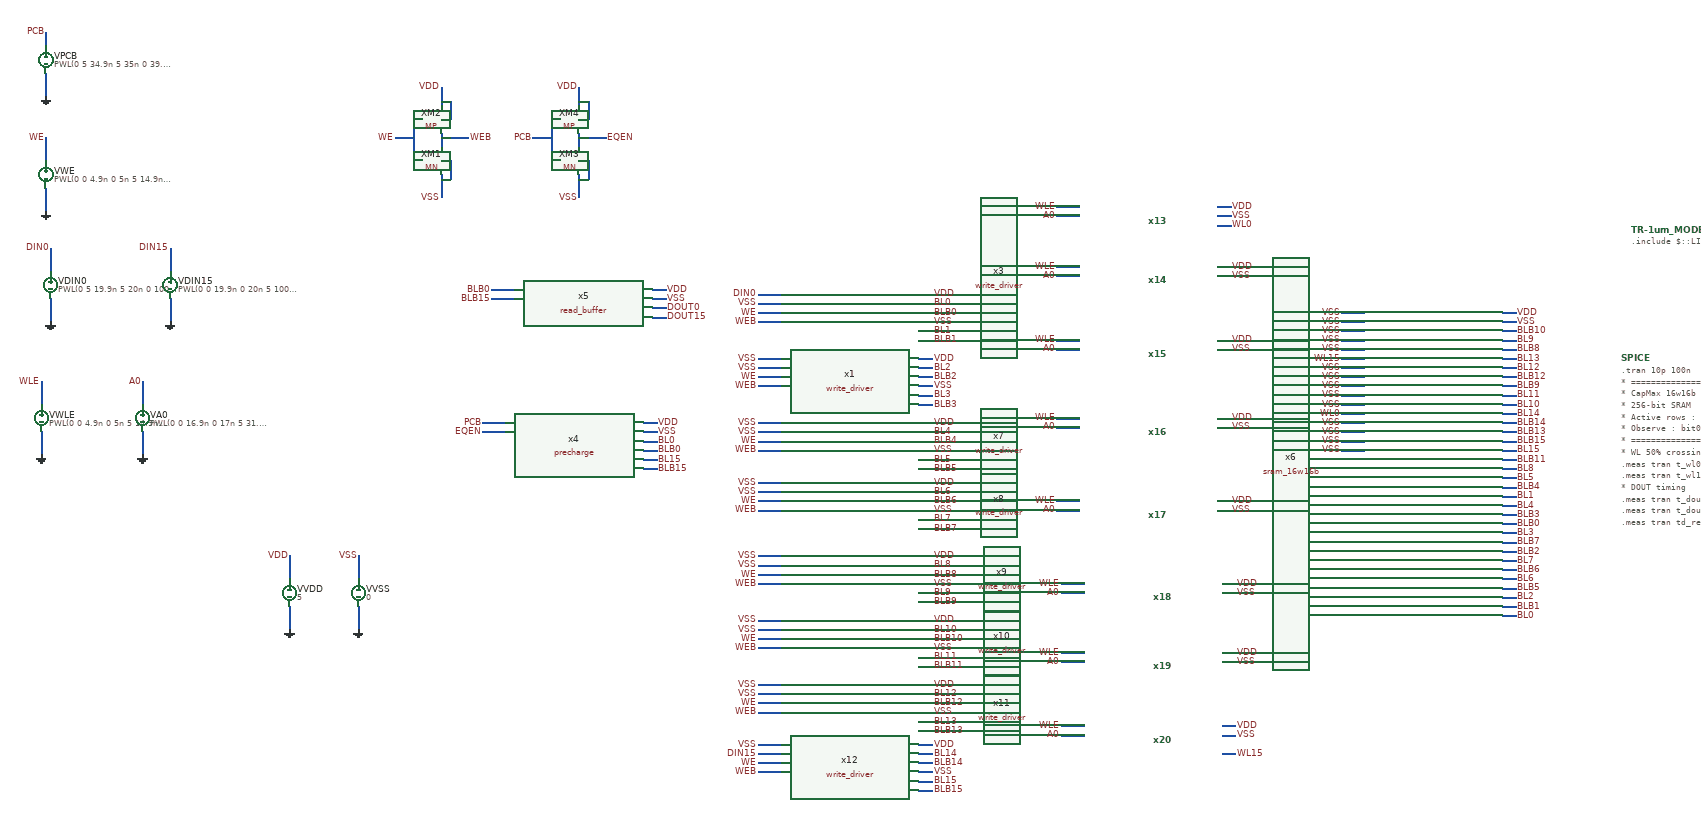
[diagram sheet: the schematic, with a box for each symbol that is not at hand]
v {xschem version=3.4.8RC file_version=1.3}
G {}
K {}
V {}
S {}
F {}
E {}
N 2980 -1010 3030 -1010 {lab=WL0}
N 2980 -990 3030 -990 {lab=WL1}
N 3330 -990 3360 -990 {lab=VSS}
N 3330 -1010 3360 -1010 {lab=VDD}
N 690 -370 690 -320 {lab=0}
N 690 -480 690 -430 {lab=VDD}
N 3330 -730 3360 -730 {lab=BLB15}
N 3330 -690 3360 -690 {lab=BLB11}
N 3330 -930 3360 -930 {lab=BLB8}
N 170 -1040 170 -990 {lab=0}
N 170 -1150 170 -1100 {lab=DIN0}
N 840 -370 840 -320 {lab=0}
N 840 -480 840 -430 {lab=VSS}
N 160 -1280 160 -1230 {lab=0}
N 160 -1390 160 -1340 {lab=WE}
N 160 -1620 160 -1590 {lab=PCB}
N 160 -1530 160 -1480 {lab=0}
N 150 -750 150 -700 {lab=0}
N 150 -860 150 -810 {lab=WLE}
N 370 -750 370 -700 {lab=0}
N 370 -860 370 -810 {lab=A0}
N 2060 -1050 2090 -1050 {lab=VDD}
N 2060 -990 2090 -990 {lab=VSS}
N 1710 -1010 1760 -1010 {lab=WE}
N 1710 -990 1760 -990 {lab=WEB}
N 2060 -1030 2090 -1030 {lab=BL0}
N 2060 -1010 2090 -1010 {lab=BLB0}
N 2060 -970 2090 -970 {lab=BL1}
N 2060 -950 2090 -950 {lab=BLB1}
N 1710 -1050 1760 -1050 {lab=DIN0}
N 1710 -1030 1760 -1030 {lab=VSS}
N 430 -1040 430 -990 {lab=0}
N 430 -1150 430 -1100 {lab=DIN15}
N 1110 -770 1160 -770 {lab=PCB}
N 1110 -750 1160 -750 {lab=EQEN}
N 1460 -770 1490 -770 {lab=VDD}
N 1460 -750 1490 -750 {lab=VSS}
N 1460 -730 1490 -730 {lab=BL0}
N 1460 -710 1490 -710 {lab=BLB0}
N 1460 -690 1490 -690 {lab=BL15}
N 1460 -670 1490 -670 {lab=BLB15}
N 1480 -1060 1510 -1060 {lab=VDD}
N 1480 -1040 1510 -1040 {lab=VSS}
N 1480 -1020 1510 -1020 {lab=DOUT0}
N 1480 -1000 1510 -1000 {lab=DOUT15}
N 1130 -1060 1180 -1060 {lab=BLB0}
N 1130 -1040 1180 -1040 {lab=BLB15}
N 1020 -1400 1020 -1370 {lab=WEB}
N 1020 -1310 1020 -1260 {lab=VSS}
N 1020 -1340 1040 -1340 {lab=VSS}
N 1040 -1340 1040 -1300 {lab=VSS}
N 1020 -1300 1040 -1300 {lab=VSS}
N 1020 -1500 1020 -1460 {lab=VDD}
N 960 -1430 980 -1430 {lab=WE}
N 960 -1430 960 -1340 {lab=WE}
N 960 -1340 980 -1340 {lab=WE}
N 1020 -1390 1080 -1390 {lab=WEB}
N 920 -1390 960 -1390 {lab=WE}
N 1020 -1430 1040 -1430 {lab=VDD}
N 1040 -1470 1040 -1430 {lab=VDD}
N 1020 -1470 1040 -1470 {lab=VDD}
N 1320 -1400 1320 -1370 {lab=EQEN}
N 1320 -1310 1320 -1260 {lab=VSS}
N 1320 -1340 1340 -1340 {lab=VSS}
N 1340 -1340 1340 -1300 {lab=VSS}
N 1320 -1300 1340 -1300 {lab=VSS}
N 1320 -1500 1320 -1460 {lab=VDD}
N 1260 -1430 1280 -1430 {lab=PCB}
N 1260 -1430 1260 -1340 {lab=PCB}
N 1260 -1340 1280 -1340 {lab=PCB}
N 1320 -1390 1380 -1390 {lab=EQEN}
N 1220 -1390 1260 -1390 {lab=PCB}
N 1320 -1430 1340 -1430 {lab=VDD}
N 1340 -1470 1340 -1430 {lab=VDD}
N 1320 -1470 1340 -1470 {lab=VDD}
N 3330 -670 3360 -670 {lab=BL8}
N 3330 -870 3360 -870 {lab=BLB12}
N 3330 -950 3360 -950 {lab=BL9}
N 3330 -970 3360 -970 {lab=BLB10}
N 3330 -830 3360 -830 {lab=BL11}
N 3330 -810 3360 -810 {lab=BL10}
N 3330 -790 3360 -790 {lab=BL14}
N 3330 -750 3360 -750 {lab=BLB13}
N 3330 -890 3360 -890 {lab=BL12}
N 3330 -850 3360 -850 {lab=BLB9}
N 3330 -770 3360 -770 {lab=BLB14}
N 3330 -710 3360 -710 {lab=BL15}
N 3330 -910 3360 -910 {lab=BL13}
N 2060 -910 2090 -910 {lab=VDD}
N 2060 -850 2090 -850 {lab=VSS}
N 1710 -870 1760 -870 {lab=WE}
N 1710 -850 1760 -850 {lab=WEB}
N 2060 -890 2090 -890 {lab=BL2}
N 2060 -870 2090 -870 {lab=BLB2}
N 2060 -830 2090 -830 {lab=BL3}
N 2060 -810 2090 -810 {lab=BLB3}
N 1710 -910 1760 -910 {lab=VSS}
N 1710 -890 1760 -890 {lab=VSS}
N 2060 -770 2090 -770 {lab=VDD}
N 2060 -710 2090 -710 {lab=VSS}
N 1710 -730 1760 -730 {lab=WE}
N 1710 -710 1760 -710 {lab=WEB}
N 2060 -750 2090 -750 {lab=BL4}
N 2060 -730 2090 -730 {lab=BLB4}
N 2060 -690 2090 -690 {lab=BL5}
N 2060 -670 2090 -670 {lab=BLB5}
N 1710 -770 1760 -770 {lab=VSS}
N 1710 -750 1760 -750 {lab=VSS}
N 2060 -640 2090 -640 {lab=VDD}
N 2060 -580 2090 -580 {lab=VSS}
N 1710 -600 1760 -600 {lab=WE}
N 1710 -580 1760 -580 {lab=WEB}
N 2060 -620 2090 -620 {lab=BL6}
N 2060 -600 2090 -600 {lab=BLB6}
N 2060 -560 2090 -560 {lab=BL7}
N 2060 -540 2090 -540 {lab=BLB7}
N 1710 -640 1760 -640 {lab=VSS}
N 1710 -620 1760 -620 {lab=VSS}
N 3330 -590 3360 -590 {lab=BL4}
N 3330 -550 3360 -550 {lab=BLB0}
N 3330 -530 3360 -530 {lab=BL3}
N 3330 -650 3360 -650 {lab=BL5}
N 3330 -610 3360 -610 {lab=BL1}
N 3330 -630 3360 -630 {lab=BLB4}
N 3330 -570 3360 -570 {lab=BLB3}
N 3330 -510 3360 -510 {lab=BLB7}
N 3330 -430 3360 -430 {lab=BL6}
N 3330 -390 3360 -390 {lab=BL2}
N 3330 -370 3360 -370 {lab=BLB1}
N 3330 -490 3360 -490 {lab=BLB2}
N 3330 -450 3360 -450 {lab=BLB6}
N 3330 -470 3360 -470 {lab=BL7}
N 3330 -410 3360 -410 {lab=BLB5}
N 3330 -350 3360 -350 {lab=BL0}
N 2060 -480 2090 -480 {lab=VDD}
N 2060 -420 2090 -420 {lab=VSS}
N 1710 -440 1760 -440 {lab=WE}
N 1710 -420 1760 -420 {lab=WEB}
N 2060 -460 2090 -460 {lab=BL8}
N 2060 -440 2090 -440 {lab=BLB8}
N 2060 -400 2090 -400 {lab=BL9}
N 2060 -380 2090 -380 {lab=BLB9}
N 1710 -480 1760 -480 {lab=VSS}
N 1710 -460 1760 -460 {lab=VSS}
N 2060 -340 2090 -340 {lab=VDD}
N 2060 -280 2090 -280 {lab=VSS}
N 1710 -300 1760 -300 {lab=WE}
N 1710 -280 1760 -280 {lab=WEB}
N 2060 -320 2090 -320 {lab=BL10}
N 2060 -300 2090 -300 {lab=BLB10}
N 2060 -260 2090 -260 {lab=BL11}
N 2060 -240 2090 -240 {lab=BLB11}
N 1710 -340 1760 -340 {lab=VSS}
N 1710 -320 1760 -320 {lab=VSS}
N 2060 -200 2090 -200 {lab=VDD}
N 2060 -140 2090 -140 {lab=VSS}
N 1710 -160 1760 -160 {lab=WE}
N 1710 -140 1760 -140 {lab=WEB}
N 2060 -180 2090 -180 {lab=BL12}
N 2060 -160 2090 -160 {lab=BLB12}
N 2060 -120 2090 -120 {lab=BL13}
N 2060 -100 2090 -100 {lab=BLB13}
N 1710 -200 1760 -200 {lab=VSS}
N 1710 -180 1760 -180 {lab=VSS}
N 2060 -70 2090 -70 {lab=VDD}
N 2060 -10 2090 -10 {lab=VSS}
N 1710 -30 1760 -30 {lab=WE}
N 1710 -10 1760 -10 {lab=WEB}
N 2060 -50 2090 -50 {lab=BL14}
N 2060 -30 2090 -30 {lab=BLB14}
N 2060 10 2090 10 {lab=BL15}
N 2060 30 2090 30 {lab=BLB15}
N 1710 -70 1760 -70 {lab=VSS}
N 1710 -50 1760 -50 {lab=DIN15}
N 2980 -970 3030 -970 {lab=WL0}
N 2980 -950 3030 -950 {lab=WL1}
N 2980 -930 3030 -930 {lab=WL0}
N 2980 -910 3030 -910 {lab=WL1}
N 2980 -890 3030 -890 {lab=WL0}
N 2980 -870 3030 -870 {lab=WL1}
N 2980 -850 3030 -850 {lab=WL0}
N 2980 -830 3030 -830 {lab=WL1}
N 2980 -810 3030 -810 {lab=WL0}
N 2980 -790 3030 -790 {lab=WL1}
N 2980 -770 3030 -770 {lab=WL0}
N 2980 -750 3030 -750 {lab=WL1}
N 2980 -730 3030 -730 {lab=WL0}
N 2980 -710 3030 -710 {lab=WL1}
N 2360 -1240 2410 -1240 {lab=WLE}
N 2360 -1220 2410 -1220 {lab=A0}
N 2710 -1240 2740 -1240 {lab=VDD}
N 2710 -1220 2740 -1220 {lab=VSS}
N 2710 -1200 2740 -1200 {lab=WL0}
N 2360 -1110 2410 -1110 {lab=WLE}
N 2360 -1090 2410 -1090 {lab=A0}
N 2710 -1110 2740 -1110 {lab=VDD}
N 2360 -950 2410 -950 {lab=WLE}
N 2360 -930 2410 -930 {lab=A0}
N 2710 -950 2740 -950 {lab=VDD}
N 2710 -930 2740 -930 {lab=VSS}
N 2360 -780 2410 -780 {lab=WLE}
N 2360 -760 2410 -760 {lab=A0}
N 2710 -780 2740 -780 {lab=VDD}
N 2710 -760 2740 -760 {lab=VSS}
N 2360 -600 2410 -600 {lab=WLE}
N 2360 -580 2410 -580 {lab=A0}
N 2710 -600 2740 -600 {lab=VDD}
N 2710 -580 2740 -580 {lab=VSS}
N 2370 -420 2420 -420 {lab=WLE}
N 2370 -400 2420 -400 {lab=A0}
N 2720 -420 2750 -420 {lab=VDD}
N 2720 -400 2750 -400 {lab=VSS}
N 2370 -270 2420 -270 {lab=WLE}
N 2370 -250 2420 -250 {lab=A0}
N 2720 -270 2750 -270 {lab=VDD}
N 2720 -250 2750 -250 {lab=VSS}
N 2370 -110 2420 -110 {lab=WLE}
N 2370 -90 2420 -90 {lab=A0}
N 2720 -110 2750 -110 {lab=VDD}
N 2720 -90 2750 -90 {lab=VSS}
N 2720 -50 2750 -50 {lab=WL15}
N 2710 -1090 2740 -1090 {lab=VSS}
C {devices/lab_pin.sym} 2980 -1010 0 0 {name=p1 sig_type=std_logic lab=VSS}
C {devices/lab_pin.sym} 2980 -990 0 0 {name=p2 sig_type=std_logic lab=VSS}
C {devices/lab_pin.sym} 3360 -1010 0 1 {name=p3 sig_type=std_logic lab=VDD}
C {devices/vsource.sym} 690 -400 0 0 {name=VVDD value=5 savecurrent=false}
C {devices/gnd.sym} 690 -320 0 0 {name=l4 lab=0}
C {devices/lab_pin.sym} 690 -480 0 0 {name=p6 sig_type=std_logic lab=VDD}
C {devices/lab_pin.sym} 3360 -730 0 1 {name=p8 sig_type=std_logic lab=BLB15}
C {devices/lab_pin.sym} 3360 -690 0 1 {name=p9 sig_type=std_logic lab=BLB11}
C {devices/lab_pin.sym} 3360 -930 0 1 {name=p10 sig_type=std_logic lab=BLB8}
C {devices/vsource.sym} 170 -1070 0 0 {name=VDIN0 value="PWL(0 5 19.9n 5 20n 0 100n 0)" savecurrent=false}
C {devices/gnd.sym} 170 -990 0 0 {name=l5 lab=0}
C {devices/lab_pin.sym} 170 -1150 0 0 {name=p35 sig_type=std_logic lab=DIN0}
C {devices/vsource.sym} 840 -400 0 0 {name=VVSS value=0 savecurrent=false}
C {devices/gnd.sym} 840 -320 0 0 {name=l9 lab=0}
C {devices/lab_pin.sym} 840 -480 0 0 {name=p43 sig_type=std_logic lab=VSS}
C {devices/lab_pin.sym} 3360 -990 0 1 {name=p39 sig_type=std_logic lab=VSS}
C {devices/vsource.sym} 160 -1310 0 0 {name=VWE value="PWL(0 0 4.9n 0 5n 5 14.9n 5 15n 0 19.9n 0 20n 5 29.9n 5 30n 0 100n 0)" savecurrent=false}
C {devices/gnd.sym} 160 -1230 0 0 {name=l1 lab=0}
C {devices/lab_pin.sym} 160 -1390 0 0 {name=p40 sig_type=std_logic lab=WE}
C {devices/code.sym} 3610 -1190 0 0 {name=TR-1um_MODELS
only_toplevel=true
format="tcleval( @value )"
value=".include $::LIB/ip62_models"
spice_ignore=false}
C {devices/code_shown.sym} 3590 -910 0 0 {name=SPICE only_toplevel=false value="
.tran 10p 100n

* ============================================================
* CapMax 16w16b SRAM Read Measurement
* 256-bit SRAM
* Active rows : WL0 and WL15
* Observe     : bit0 and bit15
* ============================================================

* WL 50% crossing
.meas tran t_wl0_rise  WHEN v(WL0)=2.5 RISE=2
.meas tran t_wl15_rise WHEN v(WL15)=2.5 RISE=2

* DOUT timing
.meas tran t_dout0_rise  WHEN v(DOUT0)=2.5 RISE=1 TD=40n
.meas tran t_dout15_rise WHEN v(DOUT15)=2.5 RISE=1 TD=65n

.meas tran td_read0  PARAM='t_dout0_rise-t_wl0_rise'
.meas tran td_read15 PARAM='t_dout15_rise-t_wl15_rise'

.control
run

plot v(pcb) v(eqen)+6
plot v(wl0) v(wl15)+6
plot v(dout0)+12 v(dout15)+18
plot v(bl0) v(blb0)
plot v(bl15) v(blb15)

.endc
"}
C {devices/vsource.sym} 160 -1560 0 0 {name=VPCB value="PWL(0 5 34.9n 5 35n 0 39.9n 0 40n 5 59.9n 5 60n 0 64.9n 0 65n 5 100n 5)" savecurrent=false}
C {devices/lab_pin.sym} 160 -1620 0 0 {name=p65 sig_type=std_logic lab=PCB}
C {devices/gnd.sym} 160 -1480 0 0 {name=l13 lab=0}
C {devices/vsource.sym} 150 -780 0 0 {name=VWLE value="PWL(0 0 4.9n 0 5n 5 14.9n 5 15n 0 19.9n 0 20n 5 29.9n 5 30n 0 44.9n 0 45n 5 54.9n 5 55n 0 69.9n 0 70n 5 79.9n 5 80n 0 100n 0)" savecurrent=false}
C {devices/gnd.sym} 150 -700 0 0 {name=l2 lab=0
value=1}
C {devices/lab_pin.sym} 150 -860 0 0 {name=p71 sig_type=std_logic lab=WLE}
C {devices/vsource.sym} 370 -780 0 0 {name=VA0 value="PWL(0 0 16.9n 0 17n 5 31.9n 5 32n 0 56.9n 0 57n 5 100n 5)" savecurrent=false}
C {devices/gnd.sym} 370 -700 0 0 {name=l3 lab=0
value=1}
C {devices/lab_pin.sym} 370 -860 0 0 {name=p72 sig_type=std_logic lab=A0}
C {write_driver.sym} 1910 -1000 0 0 {name=x3}
C {devices/lab_pin.sym} 2090 -1050 0 1 {name=p11 sig_type=std_logic lab=VDD}
C {devices/lab_pin.sym} 2090 -990 0 1 {name=p12 sig_type=std_logic lab=VSS}
C {devices/lab_pin.sym} 1710 -1010 0 0 {name=p13 sig_type=std_logic lab=WE}
C {devices/lab_pin.sym} 1710 -990 0 0 {name=p14 sig_type=std_logic lab=WEB}
C {devices/lab_pin.sym} 2090 -1030 0 1 {name=p15 sig_type=std_logic lab=BL0}
C {devices/lab_pin.sym} 2090 -1010 0 1 {name=p16 sig_type=std_logic lab=BLB0}
C {devices/lab_pin.sym} 2090 -970 0 1 {name=p17 sig_type=std_logic lab=BL1}
C {devices/lab_pin.sym} 2090 -950 0 1 {name=p18 sig_type=std_logic lab=BLB1}
C {devices/lab_pin.sym} 1710 -1050 0 0 {name=p19 sig_type=std_logic lab=DIN0}
C {devices/lab_pin.sym} 1710 -1030 0 0 {name=p20 sig_type=std_logic lab=VSS}
C {devices/vsource.sym} 430 -1070 0 0 {name=VDIN15 value="PWL(0 0 19.9n 0 20n 5 100n 5)" savecurrent=false}
C {devices/gnd.sym} 430 -990 0 0 {name=l6 lab=0}
C {devices/lab_pin.sym} 430 -1150 0 0 {name=p21 sig_type=std_logic lab=DIN15}
C {precharge.sym} 1310 -720 0 0 {name=x4}
C {devices/lab_pin.sym} 1110 -770 0 0 {name=p22 sig_type=std_logic lab=PCB}
C {devices/lab_pin.sym} 1110 -750 0 0 {name=p23 sig_type=std_logic lab=EQEN}
C {devices/lab_pin.sym} 1490 -770 0 1 {name=p24 sig_type=std_logic lab=VDD}
C {devices/lab_pin.sym} 1490 -750 0 1 {name=p25 sig_type=std_logic lab=VSS}
C {devices/lab_pin.sym} 1490 -730 0 1 {name=p26 sig_type=std_logic lab=BL0}
C {devices/lab_pin.sym} 1490 -710 0 1 {name=p27 sig_type=std_logic lab=BLB0}
C {devices/lab_pin.sym} 1490 -690 0 1 {name=p28 sig_type=std_logic lab=BL15}
C {devices/lab_pin.sym} 1490 -670 0 1 {name=p29 sig_type=std_logic lab=BLB15}
C {read_buffer.sym} 1330 -1030 0 0 {name=x5}
C {devices/lab_pin.sym} 1510 -1060 0 1 {name=p30 sig_type=std_logic lab=VDD}
C {devices/lab_pin.sym} 1510 -1040 0 1 {name=p31 sig_type=std_logic lab=VSS}
C {devices/lab_pin.sym} 1510 -1020 0 1 {name=p32 sig_type=std_logic lab=DOUT0}
C {devices/lab_pin.sym} 1510 -1000 0 1 {name=p33 sig_type=std_logic lab=DOUT15}
C {devices/lab_pin.sym} 1130 -1060 0 0 {name=p34 sig_type=std_logic lab=BLB0}
C {devices/lab_pin.sym} 1130 -1040 0 0 {name=p36 sig_type=std_logic lab=BLB15}
C {devices/lab_pin.sym} 1020 -1500 0 0 {name=p63 sig_type=std_logic lab=VDD}
C {devices/lab_pin.sym} 920 -1390 0 0 {name=p64 sig_type=std_logic lab=WE}
C {devices/lab_pin.sym} 1080 -1390 0 1 {name=p41 sig_type=std_logic lab=WEB}
C {devices/lab_pin.sym} 1020 -1260 0 0 {name=p45 sig_type=std_logic lab=VSS}
C {TR-1umLIB/MN.sym} 980 -1340 0 0 {name=XM1
model=NMOS
w=3.4u
l=1u
m=1
spiceprefix=X
as=0
ad=0
ps=0
pd=0
nrd=0
nrs=0}
C {TR-1umLIB/MP.sym} 980 -1430 0 0 {name=XM2
model=PMOS
w=6.8u
l=1u
m=1
spiceprefix=X
as=0
ad=0
ps=0
pd=0
nrd=0
nrs=0}
C {devices/lab_pin.sym} 1320 -1500 0 0 {name=p46 sig_type=std_logic lab=VDD}
C {devices/lab_pin.sym} 1220 -1390 0 0 {name=p47 sig_type=std_logic lab=PCB}
C {devices/lab_pin.sym} 1380 -1390 0 1 {name=p48 sig_type=std_logic lab=EQEN}
C {devices/lab_pin.sym} 1320 -1260 0 0 {name=p49 sig_type=std_logic lab=VSS}
C {TR-1umLIB/MN.sym} 1280 -1340 0 0 {name=XM3
model=NMOS
w=3.4u
l=1u
m=1
spiceprefix=X
as=0
ad=0
ps=0
pd=0
nrd=0
nrs=0}
C {TR-1umLIB/MP.sym} 1280 -1430 0 0 {name=XM4
model=PMOS
w=6.8u
l=1u
m=1
spiceprefix=X
as=0
ad=0
ps=0
pd=0
nrd=0
nrs=0}
C {devices/lab_pin.sym} 3360 -670 0 1 {name=p37 sig_type=std_logic lab=BL8}
C {devices/lab_pin.sym} 3360 -870 0 1 {name=p7 sig_type=std_logic lab=BLB12}
C {devices/lab_pin.sym} 3360 -950 0 1 {name=p38 sig_type=std_logic lab=BL9}
C {devices/lab_pin.sym} 3360 -970 0 1 {name=p42 sig_type=std_logic lab=BLB10}
C {devices/lab_pin.sym} 3360 -830 0 1 {name=p44 sig_type=std_logic lab=BL11}
C {devices/lab_pin.sym} 3360 -810 0 1 {name=p50 sig_type=std_logic lab=BL10}
C {devices/lab_pin.sym} 3360 -790 0 1 {name=p51 sig_type=std_logic lab=BL14}
C {devices/lab_pin.sym} 3360 -750 0 1 {name=p52 sig_type=std_logic lab=BLB13}
C {devices/lab_pin.sym} 3360 -890 0 1 {name=p53 sig_type=std_logic lab=BL12}
C {devices/lab_pin.sym} 3360 -850 0 1 {name=p54 sig_type=std_logic lab=BLB9}
C {devices/lab_pin.sym} 3360 -770 0 1 {name=p55 sig_type=std_logic lab=BLB14}
C {devices/lab_pin.sym} 3360 -710 0 1 {name=p56 sig_type=std_logic lab=BL15}
C {devices/lab_pin.sym} 3360 -910 0 1 {name=p57 sig_type=std_logic lab=BL13}
C {write_driver.sym} 1910 -860 0 0 {name=x1}
C {devices/lab_pin.sym} 2090 -910 0 1 {name=p58 sig_type=std_logic lab=VDD}
C {devices/lab_pin.sym} 2090 -850 0 1 {name=p59 sig_type=std_logic lab=VSS}
C {devices/lab_pin.sym} 1710 -870 0 0 {name=p60 sig_type=std_logic lab=WE}
C {devices/lab_pin.sym} 1710 -850 0 0 {name=p61 sig_type=std_logic lab=WEB}
C {devices/lab_pin.sym} 2090 -890 0 1 {name=p62 sig_type=std_logic lab=BL2}
C {devices/lab_pin.sym} 2090 -870 0 1 {name=p66 sig_type=std_logic lab=BLB2}
C {devices/lab_pin.sym} 2090 -830 0 1 {name=p73 sig_type=std_logic lab=BL3}
C {devices/lab_pin.sym} 2090 -810 0 1 {name=p74 sig_type=std_logic lab=BLB3}
C {devices/lab_pin.sym} 1710 -910 0 0 {name=p75 sig_type=std_logic lab=VSS}
C {devices/lab_pin.sym} 1710 -890 0 0 {name=p76 sig_type=std_logic lab=VSS}
C {write_driver.sym} 1910 -720 0 0 {name=x7}
C {devices/lab_pin.sym} 2090 -770 0 1 {name=p77 sig_type=std_logic lab=VDD}
C {devices/lab_pin.sym} 2090 -710 0 1 {name=p78 sig_type=std_logic lab=VSS}
C {devices/lab_pin.sym} 1710 -730 0 0 {name=p79 sig_type=std_logic lab=WE}
C {devices/lab_pin.sym} 1710 -710 0 0 {name=p80 sig_type=std_logic lab=WEB}
C {devices/lab_pin.sym} 2090 -750 0 1 {name=p81 sig_type=std_logic lab=BL4}
C {devices/lab_pin.sym} 2090 -730 0 1 {name=p82 sig_type=std_logic lab=BLB4}
C {devices/lab_pin.sym} 2090 -690 0 1 {name=p83 sig_type=std_logic lab=BL5}
C {devices/lab_pin.sym} 2090 -670 0 1 {name=p84 sig_type=std_logic lab=BLB5}
C {devices/lab_pin.sym} 1710 -770 0 0 {name=p85 sig_type=std_logic lab=VSS}
C {devices/lab_pin.sym} 1710 -750 0 0 {name=p86 sig_type=std_logic lab=VSS}
C {write_driver.sym} 1910 -590 0 0 {name=x8}
C {devices/lab_pin.sym} 2090 -640 0 1 {name=p87 sig_type=std_logic lab=VDD}
C {devices/lab_pin.sym} 2090 -580 0 1 {name=p88 sig_type=std_logic lab=VSS}
C {devices/lab_pin.sym} 1710 -600 0 0 {name=p89 sig_type=std_logic lab=WE}
C {devices/lab_pin.sym} 1710 -580 0 0 {name=p90 sig_type=std_logic lab=WEB}
C {devices/lab_pin.sym} 2090 -620 0 1 {name=p91 sig_type=std_logic lab=BL6}
C {devices/lab_pin.sym} 2090 -600 0 1 {name=p92 sig_type=std_logic lab=BLB6}
C {devices/lab_pin.sym} 2090 -560 0 1 {name=p93 sig_type=std_logic lab=BL7}
C {devices/lab_pin.sym} 2090 -540 0 1 {name=p94 sig_type=std_logic lab=BLB7}
C {devices/lab_pin.sym} 1710 -640 0 0 {name=p95 sig_type=std_logic lab=VSS}
C {devices/lab_pin.sym} 1710 -620 0 0 {name=p96 sig_type=std_logic lab=VSS}
C {devices/lab_pin.sym} 3360 -590 0 1 {name=p97 sig_type=std_logic lab=BL4}
C {devices/lab_pin.sym} 3360 -550 0 1 {name=p98 sig_type=std_logic lab=BLB0}
C {devices/lab_pin.sym} 3360 -530 0 1 {name=p99 sig_type=std_logic lab=BL3}
C {devices/lab_pin.sym} 3360 -650 0 1 {name=p100 sig_type=std_logic lab=BL5}
C {devices/lab_pin.sym} 3360 -610 0 1 {name=p101 sig_type=std_logic lab=BL1}
C {devices/lab_pin.sym} 3360 -630 0 1 {name=p102 sig_type=std_logic lab=BLB4}
C {devices/lab_pin.sym} 3360 -570 0 1 {name=p103 sig_type=std_logic lab=BLB3}
C {devices/lab_pin.sym} 3360 -510 0 1 {name=p104 sig_type=std_logic lab=BLB7}
C {devices/lab_pin.sym} 3360 -430 0 1 {name=p105 sig_type=std_logic lab=BL6}
C {devices/lab_pin.sym} 3360 -390 0 1 {name=p106 sig_type=std_logic lab=BL2}
C {devices/lab_pin.sym} 3360 -370 0 1 {name=p107 sig_type=std_logic lab=BLB1}
C {devices/lab_pin.sym} 3360 -490 0 1 {name=p108 sig_type=std_logic lab=BLB2}
C {devices/lab_pin.sym} 3360 -450 0 1 {name=p109 sig_type=std_logic lab=BLB6}
C {devices/lab_pin.sym} 3360 -470 0 1 {name=p110 sig_type=std_logic lab=BL7}
C {devices/lab_pin.sym} 3360 -410 0 1 {name=p111 sig_type=std_logic lab=BLB5}
C {devices/lab_pin.sym} 3360 -350 0 1 {name=p112 sig_type=std_logic lab=BL0}
C {write_driver.sym} 1910 -430 0 0 {name=x9}
C {devices/lab_pin.sym} 2090 -480 0 1 {name=p113 sig_type=std_logic lab=VDD}
C {devices/lab_pin.sym} 2090 -420 0 1 {name=p114 sig_type=std_logic lab=VSS}
C {devices/lab_pin.sym} 1710 -440 0 0 {name=p115 sig_type=std_logic lab=WE}
C {devices/lab_pin.sym} 1710 -420 0 0 {name=p116 sig_type=std_logic lab=WEB}
C {devices/lab_pin.sym} 2090 -460 0 1 {name=p117 sig_type=std_logic lab=BL8}
C {devices/lab_pin.sym} 2090 -440 0 1 {name=p118 sig_type=std_logic lab=BLB8}
C {devices/lab_pin.sym} 2090 -400 0 1 {name=p119 sig_type=std_logic lab=BL9}
C {devices/lab_pin.sym} 2090 -380 0 1 {name=p120 sig_type=std_logic lab=BLB9}
C {devices/lab_pin.sym} 1710 -480 0 0 {name=p121 sig_type=std_logic lab=VSS}
C {devices/lab_pin.sym} 1710 -460 0 0 {name=p122 sig_type=std_logic lab=VSS}
C {write_driver.sym} 1910 -290 0 0 {name=x10}
C {devices/lab_pin.sym} 2090 -340 0 1 {name=p123 sig_type=std_logic lab=VDD}
C {devices/lab_pin.sym} 2090 -280 0 1 {name=p124 sig_type=std_logic lab=VSS}
C {devices/lab_pin.sym} 1710 -300 0 0 {name=p125 sig_type=std_logic lab=WE}
C {devices/lab_pin.sym} 1710 -280 0 0 {name=p126 sig_type=std_logic lab=WEB}
C {devices/lab_pin.sym} 2090 -320 0 1 {name=p127 sig_type=std_logic lab=BL10}
C {devices/lab_pin.sym} 2090 -300 0 1 {name=p128 sig_type=std_logic lab=BLB10}
C {devices/lab_pin.sym} 2090 -260 0 1 {name=p129 sig_type=std_logic lab=BL11}
C {devices/lab_pin.sym} 2090 -240 0 1 {name=p130 sig_type=std_logic lab=BLB11}
C {devices/lab_pin.sym} 1710 -340 0 0 {name=p131 sig_type=std_logic lab=VSS}
C {devices/lab_pin.sym} 1710 -320 0 0 {name=p132 sig_type=std_logic lab=VSS}
C {write_driver.sym} 1910 -150 0 0 {name=x11}
C {devices/lab_pin.sym} 2090 -200 0 1 {name=p133 sig_type=std_logic lab=VDD}
C {devices/lab_pin.sym} 2090 -140 0 1 {name=p134 sig_type=std_logic lab=VSS}
C {devices/lab_pin.sym} 1710 -160 0 0 {name=p135 sig_type=std_logic lab=WE}
C {devices/lab_pin.sym} 1710 -140 0 0 {name=p136 sig_type=std_logic lab=WEB}
C {devices/lab_pin.sym} 2090 -180 0 1 {name=p137 sig_type=std_logic lab=BL12}
C {devices/lab_pin.sym} 2090 -160 0 1 {name=p138 sig_type=std_logic lab=BLB12}
C {devices/lab_pin.sym} 2090 -120 0 1 {name=p139 sig_type=std_logic lab=BL13}
C {devices/lab_pin.sym} 2090 -100 0 1 {name=p140 sig_type=std_logic lab=BLB13}
C {devices/lab_pin.sym} 1710 -200 0 0 {name=p141 sig_type=std_logic lab=VSS}
C {devices/lab_pin.sym} 1710 -180 0 0 {name=p142 sig_type=std_logic lab=VSS}
C {write_driver.sym} 1910 -20 0 0 {name=x12}
C {devices/lab_pin.sym} 2090 -70 0 1 {name=p143 sig_type=std_logic lab=VDD}
C {devices/lab_pin.sym} 2090 -10 0 1 {name=p144 sig_type=std_logic lab=VSS}
C {devices/lab_pin.sym} 1710 -30 0 0 {name=p145 sig_type=std_logic lab=WE}
C {devices/lab_pin.sym} 1710 -10 0 0 {name=p146 sig_type=std_logic lab=WEB}
C {devices/lab_pin.sym} 2090 -50 0 1 {name=p147 sig_type=std_logic lab=BL14}
C {devices/lab_pin.sym} 2090 -30 0 1 {name=p148 sig_type=std_logic lab=BLB14}
C {devices/lab_pin.sym} 2090 10 0 1 {name=p149 sig_type=std_logic lab=BL15}
C {devices/lab_pin.sym} 2090 30 0 1 {name=p150 sig_type=std_logic lab=BLB15}
C {devices/lab_pin.sym} 1710 -70 0 0 {name=p151 sig_type=std_logic lab=VSS}
C {devices/lab_pin.sym} 1710 -50 0 0 {name=p152 sig_type=std_logic lab=DIN15}
C {sram_16w16b.sym} 3180 -680 0 0 {name=x6}
C {devices/lab_pin.sym} 2980 -970 0 0 {name=p153 sig_type=std_logic lab=VSS}
C {devices/lab_pin.sym} 2980 -950 0 0 {name=p154 sig_type=std_logic lab=VSS}
C {devices/lab_pin.sym} 2980 -930 0 0 {name=p155 sig_type=std_logic lab=VSS}
C {devices/lab_pin.sym} 2980 -910 0 0 {name=p156 sig_type=std_logic lab=WL15}
C {devices/lab_pin.sym} 2980 -890 0 0 {name=p157 sig_type=std_logic lab=VSS}
C {devices/lab_pin.sym} 2980 -870 0 0 {name=p158 sig_type=std_logic lab=VSS}
C {devices/lab_pin.sym} 2980 -850 0 0 {name=p159 sig_type=std_logic lab=VSS}
C {devices/lab_pin.sym} 2980 -830 0 0 {name=p160 sig_type=std_logic lab=VSS}
C {devices/lab_pin.sym} 2980 -810 0 0 {name=p161 sig_type=std_logic lab=VSS}
C {devices/lab_pin.sym} 2980 -790 0 0 {name=p162 sig_type=std_logic lab=WL0}
C {devices/lab_pin.sym} 2980 -770 0 0 {name=p163 sig_type=std_logic lab=VSS}
C {devices/lab_pin.sym} 2980 -750 0 0 {name=p164 sig_type=std_logic lab=VSS}
C {devices/lab_pin.sym} 2980 -730 0 0 {name=p165 sig_type=std_logic lab=VSS}
C {devices/lab_pin.sym} 2980 -710 0 0 {name=p166 sig_type=std_logic lab=VSS}
C {decoder.sym} 2560 -1210 0 0 {name=x13}
C {devices/lab_pin.sym} 2360 -1240 0 0 {name=p167 sig_type=std_logic lab=WLE}
C {devices/lab_pin.sym} 2360 -1220 0 0 {name=p168 sig_type=std_logic lab=A0}
C {devices/lab_pin.sym} 2740 -1240 0 1 {name=p169 sig_type=std_logic lab=VDD}
C {devices/lab_pin.sym} 2740 -1220 0 1 {name=p170 sig_type=std_logic lab=VSS}
C {devices/lab_pin.sym} 2740 -1200 0 1 {name=p171 sig_type=std_logic lab=WL0}
C {decoder.sym} 2560 -1080 0 0 {name=x14}
C {devices/lab_pin.sym} 2360 -1110 0 0 {name=p172 sig_type=std_logic lab=WLE}
C {devices/lab_pin.sym} 2360 -1090 0 0 {name=p173 sig_type=std_logic lab=A0}
C {devices/lab_pin.sym} 2740 -1110 0 1 {name=p174 sig_type=std_logic lab=VDD}
C {devices/lab_pin.sym} 2740 -1090 0 1 {name=p175 sig_type=std_logic lab=VSS}
C {decoder.sym} 2560 -920 0 0 {name=x15}
C {devices/lab_pin.sym} 2360 -950 0 0 {name=p176 sig_type=std_logic lab=WLE}
C {devices/lab_pin.sym} 2360 -930 0 0 {name=p177 sig_type=std_logic lab=A0}
C {devices/lab_pin.sym} 2740 -950 0 1 {name=p178 sig_type=std_logic lab=VDD}
C {devices/lab_pin.sym} 2740 -930 0 1 {name=p179 sig_type=std_logic lab=VSS}
C {decoder.sym} 2560 -750 0 0 {name=x16}
C {devices/lab_pin.sym} 2360 -780 0 0 {name=p180 sig_type=std_logic lab=WLE}
C {devices/lab_pin.sym} 2360 -760 0 0 {name=p181 sig_type=std_logic lab=A0}
C {devices/lab_pin.sym} 2740 -780 0 1 {name=p182 sig_type=std_logic lab=VDD}
C {devices/lab_pin.sym} 2740 -760 0 1 {name=p183 sig_type=std_logic lab=VSS}
C {decoder.sym} 2560 -570 0 0 {name=x17}
C {devices/lab_pin.sym} 2360 -600 0 0 {name=p184 sig_type=std_logic lab=WLE}
C {devices/lab_pin.sym} 2360 -580 0 0 {name=p185 sig_type=std_logic lab=A0}
C {devices/lab_pin.sym} 2740 -600 0 1 {name=p186 sig_type=std_logic lab=VDD}
C {devices/lab_pin.sym} 2740 -580 0 1 {name=p187 sig_type=std_logic lab=VSS}
C {decoder.sym} 2570 -390 0 0 {name=x18}
C {devices/lab_pin.sym} 2370 -420 0 0 {name=p188 sig_type=std_logic lab=WLE}
C {devices/lab_pin.sym} 2370 -400 0 0 {name=p189 sig_type=std_logic lab=A0}
C {devices/lab_pin.sym} 2750 -420 0 1 {name=p190 sig_type=std_logic lab=VDD}
C {devices/lab_pin.sym} 2750 -400 0 1 {name=p191 sig_type=std_logic lab=VSS}
C {decoder.sym} 2570 -240 0 0 {name=x19}
C {devices/lab_pin.sym} 2370 -270 0 0 {name=p192 sig_type=std_logic lab=WLE}
C {devices/lab_pin.sym} 2370 -250 0 0 {name=p193 sig_type=std_logic lab=A0}
C {devices/lab_pin.sym} 2750 -270 0 1 {name=p194 sig_type=std_logic lab=VDD}
C {devices/lab_pin.sym} 2750 -250 0 1 {name=p195 sig_type=std_logic lab=VSS}
C {decoder.sym} 2570 -80 0 0 {name=x20}
C {devices/lab_pin.sym} 2370 -110 0 0 {name=p196 sig_type=std_logic lab=WLE}
C {devices/lab_pin.sym} 2370 -90 0 0 {name=p197 sig_type=std_logic lab=A0}
C {devices/lab_pin.sym} 2750 -110 0 1 {name=p198 sig_type=std_logic lab=VDD}
C {devices/lab_pin.sym} 2750 -90 0 1 {name=p199 sig_type=std_logic lab=VSS}
C {devices/lab_pin.sym} 2750 -50 0 1 {name=p200 sig_type=std_logic lab=WL15}
